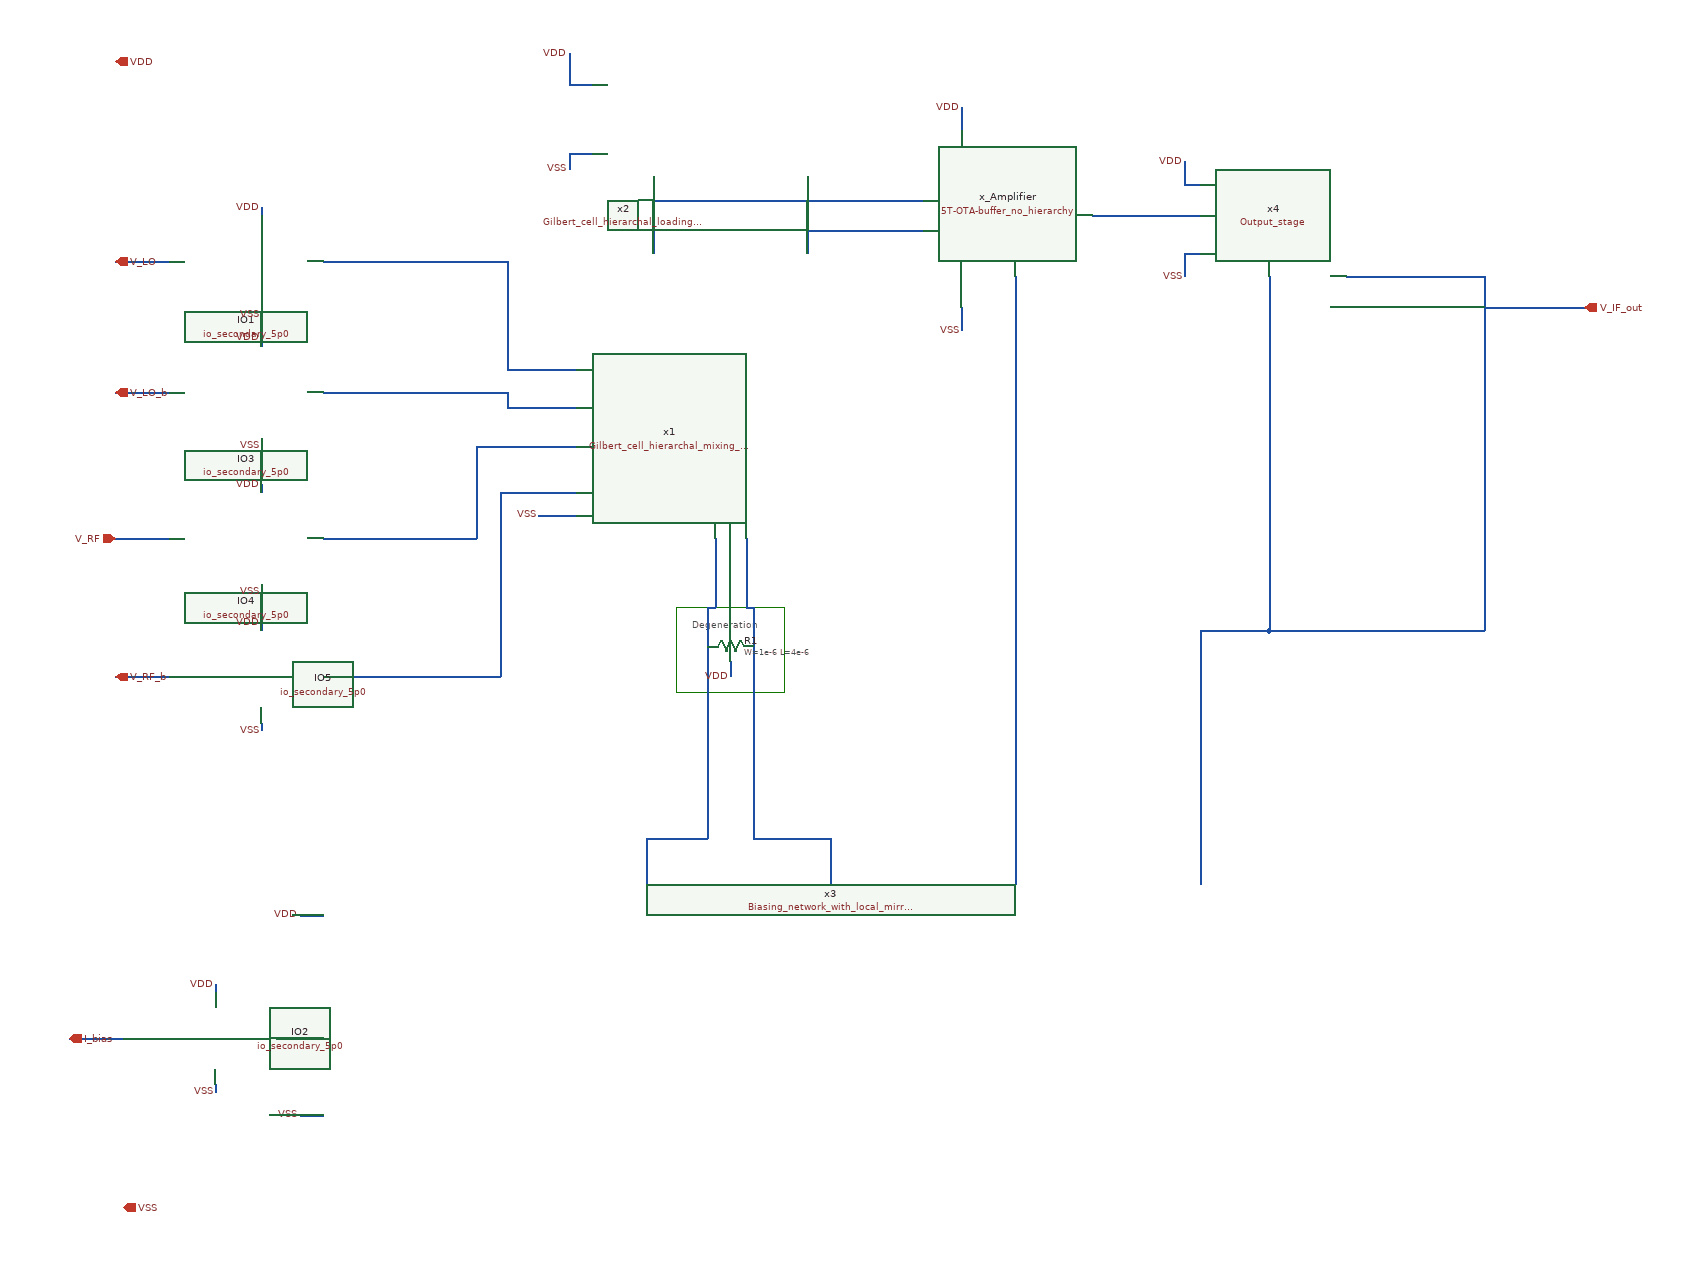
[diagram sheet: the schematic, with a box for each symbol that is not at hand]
v {xschem version=3.4.5 file_version=1.2
}
G {}
K {}
V {}
S {}
E {}
P 4 5 1340 -1230 1480 -1230 1480 -1120 1340 -1120 1340 -1230 {}
T {Degeneration} 1360 -1220 0 0 0.3 0.3 {}
N 1390 -1320 1390 -1280 {
lab=#net1}
N 1390 -1280 1390 -1260 {
lab=#net1}
N 1430 -1320 1430 -1260 {
lab=#net2}
N 1310 -1790 1310 -1690 {
lab=#net3}
N 1510 -1790 1510 -1690 {
lab=#net4}
N 1120 -1490 1210 -1490 {
lab=#net5}
N 1120 -1540 1210 -1540 {
lab=#net6}
N 1120 -1440 1210 -1440 {
lab=#net7}
N 1120 -1380 1210 -1380 {
lab=#net8}
N 1390 -1260 1390 -1230 {
lab=#net1}
N 1430 -1260 1430 -1230 {
lab=#net2}
N 1380 -1180 1380 -1120 {
lab=#net1}
N 1440 -1180 1440 -1130 {
lab=#net2}
N 1380 -1230 1380 -1180 {
lab=#net1}
N 1380 -1230 1390 -1230 {
lab=#net1}
N 1440 -1230 1440 -1180 {
lab=#net2}
N 1430 -1230 1440 -1230 {
lab=#net2}
N 1440 -1130 1440 -1120 {
lab=#net2}
N 1300 -930 1300 -870 {
lab=#net1}
N 1300 -930 1380 -930 {
lab=#net1}
N 1540 -930 1540 -870 {
lab=#net2}
N 1440 -930 1540 -930 {
lab=#net2}
N 1780 -920 1780 -870 {
lab=#net9}
N 850 -830 880 -830 {
lab=VDD}
N 850 -570 880 -570 {
lab=VSS}
N 1380 -1120 1380 -1020 {
lab=#net1}
N 1440 -1120 1440 -1020 {
lab=#net2}
N 1380 -960 1380 -930 {
lab=#net1}
N 1440 -960 1440 -930 {
lab=#net2}
N 610 -1680 640 -1680 {
lab=V_LO}
N 610 -1510 640 -1510 {
lab=V_LO_b}
N 610 -1140 640 -1140 {
lab=V_RF_b}
N 1120 -1680 1120 -1540 {
lab=#net6}
N 1120 -1510 1120 -1490 {
lab=#net5}
N 1080 -1440 1080 -1320 {
lab=#net7}
N 1080 -1440 1120 -1440 {
lab=#net7}
N 1110 -1380 1110 -1140 {
lab=#net8}
N 1110 -1380 1120 -1380 {
lab=#net8}
N 2480 -1620 2520 -1620 {
lab=V_IF_out}
N 1520 -1720 1640 -1720 {
lab=#net4}
N 1520 -1760 1640 -1760 {
lab=#net3}
N 1510 -1720 1520 -1720 {
lab=#net4}
N 1310 -1760 1520 -1760 {
lab=#net3}
N 2390 -1620 2480 -1620 {
lab=V_IF_out}
N 2020 -1200 2020 -870 {
lab=V_IF_out}
N 550 -670 580 -670 {
lab=I_bias}
N 1160 -1350 1210 -1350 {
lab=VSS}
N 1380 -1020 1380 -960 {
lab=#net1}
N 1440 -1020 1440 -960 {
lab=#net2}
N 2020 -1200 2110 -1200 {
lab=V_IF_out}
N 2110 -1200 2390 -1200 {
lab=V_IF_out}
N 740 -610 740 -600 {
lab=VSS}
N 650 -1680 680 -1680 {
lab=V_LO}
N 650 -1320 680 -1320 {
lab=V_RF}
N 650 -1140 680 -1140 {
lab=V_RF_b}
N 740 -740 740 -730 {
lab=VDD}
N 800 -1210 800 -1200 {
lab=VDD}
N 800 -1390 800 -1380 {
lab=VDD}
N 800 -1580 800 -1570 {
lab=VDD}
N 800 -1750 800 -1740 {
lab=VDD}
N 800 -1080 800 -1070 {
lab=VSS}
N 800 -1260 800 -1250 {
lab=VSS}
N 800 -1450 800 -1440 {
lab=VSS}
N 800 -1620 800 -1610 {
lab=VSS}
N 640 -1680 650 -1680 {
lab=V_LO}
N 880 -1680 1120 -1680 {
lab=#net6}
N 640 -1510 680 -1510 {
lab=V_LO_b}
N 880 -1510 1120 -1510 {
lab=#net5}
N 610 -1320 650 -1320 {
lab=V_RF}
N 880 -1320 1080 -1320 {
lab=#net7}
N 640 -1140 650 -1140 {
lab=V_RF_b}
N 880 -1140 1110 -1140 {
lab=#net8}
N 580 -670 620 -670 {
lab=I_bias}
N 820 -670 880 -670 {
lab=#net10}
N 1410 -1160 1410 -1140 {
lab=VDD}
N 1780 -1640 1780 -920 {
lab=#net9}
N 1780 -1660 1780 -1640 {
lab=#net9}
N 1880 -1740 2020 -1740 {
lab=#net11}
N 1640 -1760 1660 -1760 {
lab=#net3}
N 1640 -1720 1660 -1720 {
lab=#net4}
N 1710 -1880 1710 -1850 {
lab=VDD}
N 1710 -1620 1710 -1590 {
lab=VSS}
N 1200 -1910 1230 -1910 {
lab=VDD}
N 1200 -1950 1200 -1910 {
lab=VDD}
N 1200 -1820 1230 -1820 {
lab=VSS}
N 1200 -1820 1200 -1800 {
lab=VSS}
N 2110 -1660 2110 -1200 {
lab=V_IF_out}
N 2210 -1660 2390 -1660 {
lab=V_IF_out}
N 2390 -1660 2390 -1200 {
lab=V_IF_out}
N 2000 -1690 2020 -1690 {
lab=#net12}
N 2000 -1690 2000 -1660 {
lab=#net12}
N 2000 -1780 2020 -1780 {
lab=VDD}
N 2000 -1810 2000 -1780 {
lab=VDD}
C {title-2.sym} 0 0 0 0 {name=l9 author="Time Transcenders" lock=true rev=1.0 page=1}
C {ipin.sym} 610 -1680 2 1 {name=p1 lab=V_LO}
C {ipin.sym} 610 -1510 2 1 {name=p2 lab=V_LO_b
}
C {ipin.sym} 610 -1320 0 0 {name=p3 lab=V_RF}
C {ipin.sym} 610 -1140 2 1 {name=p4 lab=V_RF_b
}
C {/home/vasil/Downloads/SSCS_PICO_2025/src/design_xsch/Gilbert_cell_hierarchal_mixing_stage.sym} 1410 -1490 0 0 {name=x1}
C {/home/vasil/Downloads/SSCS_PICO_2025/src/design_xsch/Biasing_network_with_local_mirros.sym} 1140 -660 0 0 {name=x3
pmos_l_ref=0.4u pmos_w_ref=2u pmos_l_mir=0.4u pmos_w_mir=8u
nmos_l_ref_1=1u nmos_w_ref_1=1.5u nmos_nf_ref_1=1 nmos_l_mir_1=1u nmos_w_mir_1=7.5u nmos_nf_mir_1=5
nmos_l_ref_2=1u nmos_w_ref_2=1.5u nmos_nf_ref_2=1 nmos_l_mir_2=1u nmos_w_mir_2=7.5u nmos_nf_mir_2=5
nmos_l_ref_3=1u nmos_w_ref_3=1.5u nmos_nf_ref_3=1 nmos_l_mir_3=1u nmos_w_mir_3=6u nmos_nf_mir_3=4
nmos_l_ref_4=1u nmos_w_ref_4=1.5u nmos_nf_ref_4=1 nmos_l_mir_4=1u nmos_w_mir_4=15u nmos_nf_mir_4=10}
C {opin.sym} 2520 -1620 0 0 {name=p5 lab=V_IF_out}
C {ipin.sym} 550 -670 2 1 {name=p18 lab=I_bias
}
C {ipin.sym} 620 -450 2 1 {name=p8 lab=VSS
}
C {ipin.sym} 610 -1940 2 1 {name=p9 lab=VDD
}
C {lab_pin.sym} 850 -570 0 0 {name=p11 sig_type=std_logic lab=VSS}
C {lab_pin.sym} 1160 -1350 0 0 {name=p23 sig_type=std_logic lab=VSS}
C {lab_pin.sym} 850 -830 0 0 {name=p29 sig_type=std_logic lab=VDD}
C {/home/vasil/Downloads/SSCS_PICO_2025/src/design_padring/Chipathon2025_pads/xschem/symbols/io_secondary_5p0/io_secondary_5p0.sym} 880 -1600 0 1 {name=IO1
spiceprefix=X
}
C {/home/vasil/Downloads/SSCS_PICO_2025/src/design_padring/Chipathon2025_pads/xschem/symbols/io_secondary_5p0/io_secondary_5p0.sym} 820 -590 0 1 {name=IO2
spiceprefix=X
}
C {/home/vasil/Downloads/SSCS_PICO_2025/src/design_padring/Chipathon2025_pads/xschem/symbols/io_secondary_5p0/io_secondary_5p0.sym} 880 -1430 0 1 {name=IO3
spiceprefix=X
}
C {/home/vasil/Downloads/SSCS_PICO_2025/src/design_padring/Chipathon2025_pads/xschem/symbols/io_secondary_5p0/io_secondary_5p0.sym} 880 -1240 0 1 {name=IO4
spiceprefix=X
}
C {/home/vasil/Downloads/SSCS_PICO_2025/src/design_padring/Chipathon2025_pads/xschem/symbols/io_secondary_5p0/io_secondary_5p0.sym} 880 -1060 0 1 {name=IO5
spiceprefix=X
}
C {lab_pin.sym} 740 -740 0 0 {name=p6 sig_type=std_logic lab=VDD}
C {lab_pin.sym} 800 -1210 0 0 {name=p12 sig_type=std_logic lab=VDD}
C {lab_pin.sym} 800 -1390 0 0 {name=p13 sig_type=std_logic lab=VDD}
C {lab_pin.sym} 800 -1580 0 0 {name=p14 sig_type=std_logic lab=VDD}
C {lab_pin.sym} 800 -1750 0 0 {name=p16 sig_type=std_logic lab=VDD}
C {lab_pin.sym} 740 -600 0 0 {name=p7 sig_type=std_logic lab=VSS}
C {lab_pin.sym} 800 -1070 0 0 {name=p10 sig_type=std_logic lab=VSS}
C {lab_pin.sym} 800 -1250 0 0 {name=p15 sig_type=std_logic lab=VSS}
C {lab_pin.sym} 800 -1440 0 0 {name=p17 sig_type=std_logic lab=VSS}
C {lab_pin.sym} 800 -1610 0 0 {name=p19 sig_type=std_logic lab=VSS}
C {symbols/ppolyf_u.sym} 1410 -1180 3 0 {name=R1
W=1e-6
L=4e-6
model=ppolyf_u
spiceprefix=X
m=1
hide_texts=True}
C {lab_pin.sym} 1410 -1140 0 0 {name=p20 sig_type=std_logic lab=VDD}
C {/home/vasil/Downloads/SSCS_PICO_2025/src/design_xsch/5T-OTA-buffer_no_hierarchy.sym} 1780 -1740 0 0 {name=x_Amplifier}
C {lab_pin.sym} 1710 -1880 0 0 {name=p21 sig_type=std_logic lab=VDD}
C {lab_pin.sym} 1710 -1590 0 0 {name=p22 sig_type=std_logic lab=VSS}
C {/home/vasil/Downloads/SSCS_PICO_2025/src/design_xsch/Gilbert_cell_hierarchal_loading_stage.sym} 1410 -1840 0 0 {name=x2}
C {lab_pin.sym} 1200 -1950 0 0 {name=p24 sig_type=std_logic lab=VDD}
C {lab_pin.sym} 1200 -1800 0 0 {name=p25 sig_type=std_logic lab=VSS}
C {/home/vasil/Downloads/SSCS_PICO_2025/src/design_xsch/Output_stage.sym} 2150 -1720 0 0 {name=x4}
C {lab_pin.sym} 2000 -1810 0 0 {name=p26 sig_type=std_logic lab=VDD}
C {lab_pin.sym} 2000 -1660 0 0 {name=p27 sig_type=std_logic lab=VSS}
